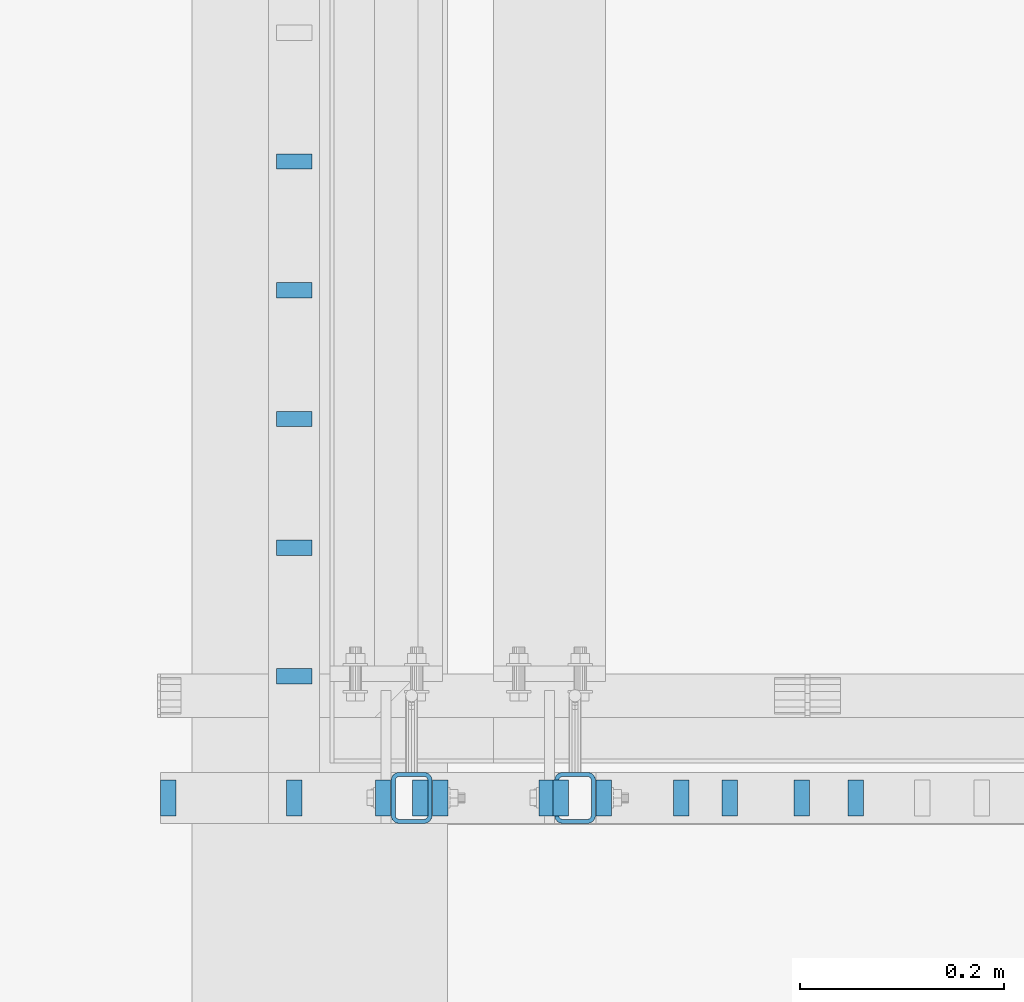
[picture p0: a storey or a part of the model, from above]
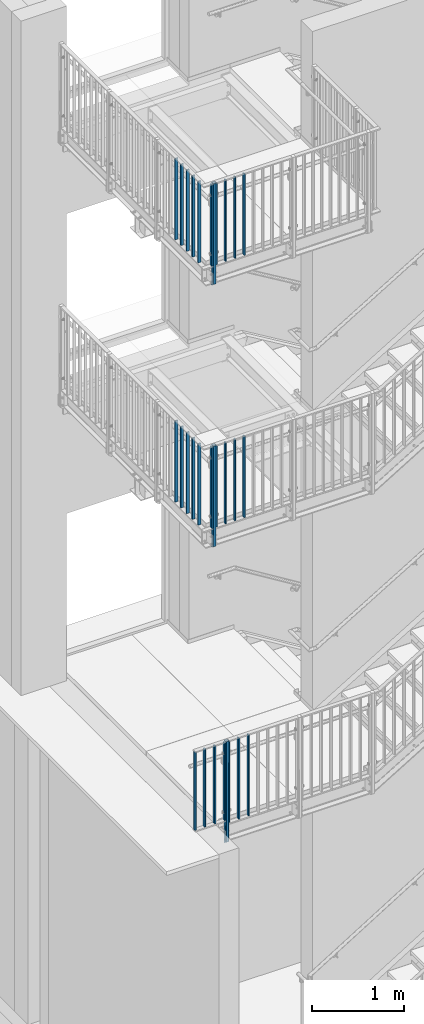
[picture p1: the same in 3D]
Properties of the parts of a building model (IFC2X3)

# File
Description: ViewDefinition[CoordinationView_V2.0]
File name: Fluchttreppe an Verwaltungsgeb?ude_ifc2x3.ifc
Time: 2026-07-12T18:16:53
Organization: medius KLINIKEN gGmbH
Written by: IFC Toolkit 2.0.26.0
Made in: Advance Steel 2024

# IfcBuildingStorey, Default Storey
In: Struktur 1
Elevation: 0 mm

# IfcBeam: - (312)
In: Default Storey
Name | Description = Section | Material | SectionFamily
2 x - | HEA240 | S235JR | HEA DIN18800-1 | Pset_BeamCommon - Reference: 16; Span: 1440 mm; Slope: 0 deg; IsExternal: no; LoadBearing: no
- | HEA240 | S235JR | HEA DIN18800-1 | Pset_BeamCommon - Reference: 32; Span: 1460 mm; Slope: 0 deg; IsExternal: no; LoadBearing: no
62 x - | FL40x3 | S235JR | Flat nach DIN
3 x - | IPE220 | S235JR | IPE DIN18800-1 | Pset_BeamCommon - Reference: 7; Span: 2890 mm; Slope: 0 deg; IsExternal: no; LoadBearing: no
16 x - | U220 | S235JR | Channels DIN18800-1
2 x - | IPE220 | S235JR | IPE DIN18800-1 | Pset_BeamCommon - Reference: 20; Span: 3015 mm; Slope: 0 deg; IsExternal: no; LoadBearing: no
- | IPE220 | S235JR | IPE DIN18800-1 | Pset_BeamCommon - Reference: 35; Span: 3015 mm; Slope: 0 deg; IsExternal: no; LoadBearing: no
2 x - | IPE220 | S235JR | IPE DIN18800-1 | Pset_BeamCommon - Reference: 21; Span: 3015 mm; Slope: 0 deg; IsExternal: no; LoadBearing: no
- | IPE220 | S235JR | IPE DIN18800-1 | Pset_BeamCommon - Reference: 36; Span: 3015 mm; Slope: 0 deg; IsExternal: no; LoadBearing: no
- | IPE220 | S235JR | IPE DIN18800-1 | Pset_BeamCommon - Reference: 37; Span: 1265 mm; Slope: 0 deg; IsExternal: no; LoadBearing: no
- | IPE220 | S235JR | IPE DIN18800-1 | Pset_BeamCommon - Reference: 34; Span: 1390 mm; Slope: 0 deg; IsExternal: no; LoadBearing: no
2 x - | IPE220 | S235JR | IPE DIN18800-1
- | IPE220 | S235JR | IPE DIN18800-1 | Pset_BeamCommon - Reference: 38; Span: 3015 mm; Slope: 0 deg; IsExternal: no; LoadBearing: no
2 x - | U220 | S235JR | Channels DIN18800-1 | Pset_BeamCommon - Reference: 24; Span: 1974.1 mm; Slope: 0 deg; IsExternal: no; LoadBearing: no
3 x - | U220 | S235JR | Channels DIN18800-1 | Pset_BeamCommon - Reference: 10; Span: 1274.1 mm; Slope: 0 deg; IsExternal: no; LoadBearing: no
4 x - | IPE160 | S235JR | IPE DIN18800-1 | Pset_BeamCommon - Reference: 5; Span: 964.1 mm; Slope: 0 deg; IsExternal: no; LoadBearing: no
2 x - | IPE160 | S235JR | IPE DIN18800-1 | Pset_BeamCommon - Reference: 18; Span: 884.1 mm; Slope: 0 deg; IsExternal: no; LoadBearing: no
2 x - | IPE160 | S235JR | IPE DIN18800-1 | Pset_BeamCommon - Reference: 19; Span: 1264.1 mm; Slope: 0 deg; IsExternal: no; LoadBearing: no
76 x - | FL50X4 | S235JR | Flat nach DIN
16 x - | FL35X15 | S235JR | Flat nach DIN
4 x - | FL50X15 | S235JR | Flat nach DIN | Pset_BeamCommon - Reference: 4; Span: 1009 mm; Slope: 0 deg; IsExternal: no; LoadBearing: no
32 x - | FL50X15 | S235JR | Flat nach DIN
3 x - | FL50X15 | S235JR | Flat nach DIN | Pset_BeamCommon - Reference: 6; Span: 959 mm; Slope: 0 deg; IsExternal: no; LoadBearing: no
- | FL50X15 | S235JR | Flat nach DIN | Pset_BeamCommon - Reference: 31; Span: 909 mm; Slope: 0 deg; IsExternal: no; LoadBearing: no
2 x - | FL50X15 | S235JR | Flat nach DIN | Pset_BeamCommon - Reference: 13; Span: 983.5 mm; Slope: 0 deg; IsExternal: no; LoadBearing: no
6 x - | FL50X15 | S235JR | Flat nach DIN | Pset_BeamCommon - Reference: 2; Span: 879 mm; Slope: 0 deg; IsExternal: no; LoadBearing: no
44 x - | RO42.4X3.2 |  | Pipe nach DIN
2 x - | HEA240 | S235JR | HEA DIN18800-1 | Pset_BeamCommon - Reference: 17; Span: 2140 mm; Slope: 0 deg; IsExternal: no; LoadBearing: no
2 x - | IPE220 | S235JR | IPE DIN18800-1 | Pset_BeamCommon - Reference: 22; Span: 3015 mm; Slope: 0 deg; IsExternal: no; LoadBearing: no
- | HEA240 | S235JR | HEA DIN18800-1 | Pset_BeamCommon - Reference: 33; Span: 1980 mm; Slope: 0 deg; IsExternal: no; LoadBearing: no
- | IPE220 | S235JR | IPE DIN18800-1 | Pset_BeamCommon - Reference: 39; Span: 3015 mm; Slope: 0 deg; IsExternal: no; LoadBearing: no
- | U220 | S235JR | Channels DIN18800-1 | Pset_BeamCommon - Reference: 57; Span: 2110 mm; Slope: 0 deg; IsExternal: no; LoadBearing: no
- | U220 | S235JR | Channels DIN18800-1 | Pset_BeamCommon - Reference: 67; Span: 1814.1 mm; Slope: 0 deg; IsExternal: no; LoadBearing: no
4 x - | FL50X5 | S235JR | Flat nach DIN
2 x - | FL50X15 | S235JR | Flat nach DIN | Pset_BeamCommon - Reference: 11; Span: 879 mm; Slope: 0 deg; IsExternal: no; LoadBearing: no
2 x - | RO42.4X3.2 |  | Pipe nach DIN | Pset_BeamCommon - Reference: 23; Span: 3070.2 mm; Slope: 0 deg; IsExternal: no; LoadBearing: no
3 x - | RO42.4X3.2 |  | Pipe nach DIN | Pset_BeamCommon - Reference: 9; Span: 2850.2 mm; Slope: 0 deg; IsExternal: no; LoadBearing: no
- | RO42.4X3.2 |  | Pipe nach DIN | Pset_BeamCommon - Reference: 53; Span: 1596.1 mm; Slope: 0 deg; IsExternal: no; LoadBearing: no

# IfcBuildingElementProxy: - (164)
In: Default Storey
Name
6 x  | Material: Kein
158 x 

# IfcColumn: - (288)
In: Default Storey
Name | Description = Section | Material | SectionFamily
2 x - | U220 | S235JR | Channels DIN18800-1
23 x - | R50X40X4 | S235JR | RHS_Sections_rectang_c nach DIN | Pset_ColumnCommon - Reference: 1; Slope: 0 deg; IsExternal: no; LoadBearing: no
6 x - | R50X40X4 | S235JR | RHS_Sections_rectang_c nach DIN | Pset_ColumnCommon - Reference: 3; Slope: 0 deg; IsExternal: no; LoadBearing: no
- | R50X40X4 | S235JR | RHS_Sections_rectang_c nach DIN | Pset_ColumnCommon - Reference: 40; Slope: 0 deg; IsExternal: no; LoadBearing: no
3 x - | R50X40X4 | S235JR | RHS_Sections_rectang_c nach DIN | Pset_ColumnCommon - Reference: 8; Slope: 0 deg; IsExternal: no; LoadBearing: no
248 x - | FL35X15 | S235JR | Flat nach DIN
- | FL35X15 | S235JR | Flat nach DIN | Pset_ColumnCommon - Reference: 26; Slope: 0 deg; IsExternal: no; LoadBearing: no
- | FL35X15 | S235JR | Flat nach DIN | Pset_ColumnCommon - Reference: 27; Slope: 0 deg; IsExternal: no; LoadBearing: no
2 x - | RO42.4X3.2 |  | Pipe nach DIN
- | FL35X15 | S235JR | Flat nach DIN | Pset_ColumnCommon - Reference: 25; Slope: 0 deg; IsExternal: no; LoadBearing: no

# IfcMechanicalFastener: - (165)
In: Default Storey
Name | NominalDiameter (mm) | NominalLength (mm)
2 x  | 20 | 95
16 x  | 16 | 40
33 x  | 12 | 70
27 x  | 8 | 30
36 x  | 20 | 50
18 x  | 12 | 45
26 x  | 10 | 90
7 x  | 10 | 75

# IfcMechanicalFastener: Anchor_Bolt#1 (2)
In: Default Storey
NominalDiameter: 16 mm; NominalLength: 150 mm

# IfcMechanicalFastener: Bolt (300)
In: Default Storey
NominalDiameter: 12 mm
Name | NominalLength (mm)
248 x  | 35
52 x  | 45

# IfcMechanicalFastener: Bolt#1 (29)
In: Default Storey
NominalDiameter: 16 mm; NominalLength: 50 mm

# IfcMember: - (49)
In: Default Storey
Name | Description = Section | Material | Reference | Span (mm) | Slope (deg) | IsExternal = LoadBearing | SectionFamily
- | U220 | S235JR | 58 | 4183.51 | 0 | no | Channels DIN18800-1
- | U220 | S235JR | 59 | 4148.66 | 0 | no | Channels DIN18800-1
- | U220 | S235JR | 60 | 3109.63 | 0 | no | Channels DIN18800-1
- | U220 | S235JR | 61 | 3997.44 | 0 | no | Channels DIN18800-1
- | U220 | S235JR | 62 | 3810.51 | 0 | no | Channels DIN18800-1
- | U220 | S235JR | 63 | 3817.66 | 0 | no | Channels DIN18800-1
- | U220 | S235JR | 64 | 4183.51 | 0 | no | Channels DIN18800-1
- | U220 | S235JR | 65 | 4148.66 | 0 | no | Channels DIN18800-1
- | U220 | S235JR | 66 | 3109.63 | 0 | no | Channels DIN18800-1
2 x - | FL50X15 | S235JR | 14 | 1176.12 | 0 | no | Flat nach DIN
13 x - | FL50X15 | S235JR |  |  |  |  | Flat nach DIN
2 x - | FL50X15 | S235JR | 12 | 1167.53 | 0 | no | Flat nach DIN
2 x - | FL50X15 | S235JR | 15 | 1169.43 | 0 | no | Flat nach DIN
- | U220 | S235JR | 54 | 3997.44 | 0 | no | Channels DIN18800-1
- | U220 | S235JR | 55 | 3780.56 | 0 | no | Channels DIN18800-1
- | U220 | S235JR | 56 | 3787.05 | 0 | no | Channels DIN18800-1
3 x - | FL50X5 | S235JR |  |  |  |  | Flat nach DIN
- | FL50X15 | S235JR | 28 | 1169.43 | 0 | no | Flat nach DIN
- | FL50X15 | S235JR | 29 | 1167.53 | 0 | no | Flat nach DIN
- | FL50X15 | S235JR | 30 | 1070.39 | 0 | no | Flat nach DIN
- | RO42.4X3.2 |  | 43 | 3060.19 | 0 | no | Pipe nach DIN
- | RO42.4X3.2 |  | 47 | 3060.19 | 0 | no | Pipe nach DIN
- | RO42.4X3.2 |  | 42 | 4069.54 | 0 | no | Pipe nach DIN
- | RO42.4X3.2 |  | 48 | 4069.54 | 0 | no | Pipe nach DIN
- | RO42.4X3.2 |  | 41 | 4100.29 | 0 | no | Pipe nach DIN
- | RO42.4X3.2 |  | 49 | 4100.29 | 0 | no | Pipe nach DIN
- | RO42.4X3.2 |  | 46 | 3737.62 | 0 | no | Pipe nach DIN
- | RO42.4X3.2 |  | 50 | 3737.62 | 0 | no | Pipe nach DIN
- | RO42.4X3.2 |  | 45 | 3731.39 | 0 | no | Pipe nach DIN
- | RO42.4X3.2 |  | 51 | 3731.39 | 0 | no | Pipe nach DIN
- | RO42.4X3.2 |  | 44 | 4207.16 | 0 | no | Pipe nach DIN
- | RO42.4X3.2 |  | 52 | 4213.03 | 0 | no | Pipe nach DIN

# IfcPlate: - (140)
In: Default Storey
Description: -
Pset_PlateCommon - IsExternal: no; LoadBearing: no
Name | Material | Reference
6 x - | S235JR 20 mm | 237
18 x - | S235JR 15 mm | 230
6 x - | S235JR 25 mm | 238
6 x - | S235JR 25 mm | 240
2 x - | S235JR 30 mm | 244
6 x - | S235JR 25 mm | 241
6 x - | S235JR 25 mm | 239
6 x - | S235JR 10 mm | 235
2 x - | S235JR 30 mm | 245
16 x - | S235JR 10 mm | 231
24 x - | S235JR 10 mm | 227
- | S235JR 10 mm | 247
6 x - | S235JR 10 mm | 234
2 x - | S235JR 10 mm | 242
23 x - | S235JR 5 mm | 229
10 x - | S235JR 5 mm | 233

# IfcPlate: Baseplate (2)
In: Default Storey
Description: -; Material: S235JR 20 mm
Pset_PlateCommon - Reference: 243; IsExternal: no; LoadBearing: no

# IfcPlate: Grate_Step#1 (62)
In: Default Storey
Description: -; Material: S235JR 40 mm
Pset_PlateCommon - IsExternal: no; LoadBearing: no
Name | Reference
53 x Grate_Step#1 | 68
9 x Grate_Step#1 | 70

# IfcPlate: Grate_Step#2 (62)
In: Default Storey
Description: -; Material: S235JR 3 mm
Pset_PlateCommon - Reference: 226; IsExternal: no; LoadBearing: no

# IfcPlate: Grate_Step#3 (62)
In: Default Storey
Description: -; Material: S235JR 3 mm
Pset_PlateCommon - Reference: 226; IsExternal: no; LoadBearing: no

# IfcPlate: Grating (24)
In: Default Storey
Description: -; Material: S235JR 60 mm
Pset_PlateCommon - IsExternal: no; LoadBearing: no
Name | Reference
2 x Grating | 71
2 x Grating | 72
Grating | 81
Grating | 82
2 x Grating | 73
2 x Grating | 74
2 x Grating | 75
Grating | 83
Grating | 84
Grating | 85
Grating | 86
Grating | 87
Grating | 88
Grating | 89
Grating | 76
Grating | 77
Grating | 78
Grating | 79
Grating | 80

# IfcPlate: LugPlate#1 (29)
In: Default Storey
Description: -; Material: S235JR 15 mm
Pset_PlateCommon - IsExternal: no; LoadBearing: no
Name | Reference
23 x LugPlate#1 | 228
6 x LugPlate#1 | 236

# IfcPlate: Stiffener#0 (9)
In: Default Storey
Description: -; Material: S235JR 6 mm
Pset_PlateCommon - IsExternal: no; LoadBearing: no
Name | Reference
8 x Stiffener#0 | 232
Stiffener#0 | 246

# IfcPlate: Stiffener#1 (9)
In: Default Storey
Description: -; Material: S235JR 6 mm
Pset_PlateCommon - IsExternal: no; LoadBearing: no
Name | Reference
8 x Stiffener#1 | 232
Stiffener#1 | 246

# IfcSlab: - (11)
In: Default Storey
Description: -
Pset_SlabCommon - Reference: nicht definiert; IsExternal: no; LoadBearing: no; Combustible: no; Compartmentation: no; PitchAngle: 0 deg
Name | Material
3 x - | C25/30 100 mm
3 x - | C25/30 400 mm
- | C25/30 200 mm
- | C25/30 120 mm
- | C25/30 350 mm
- | C25/30 420 mm
- | C25/30 50 mm

# IfcWall: - (32)
In: Default Storey
Description: -
Pset_WallCommon - Reference: nicht definiert; Combustible: no; IsExternal: no; ExtendToStructure: no; LoadBearing: no; Compartmentation: no
Name | Material
15 x - | C25/30 300 mm
2 x - | C25/30 250 mm
6 x - | C25/30 75 mm
4 x - | C25/30 225 mm
- | C25/30 150 mm
4 x - | C25/30 210 mm
